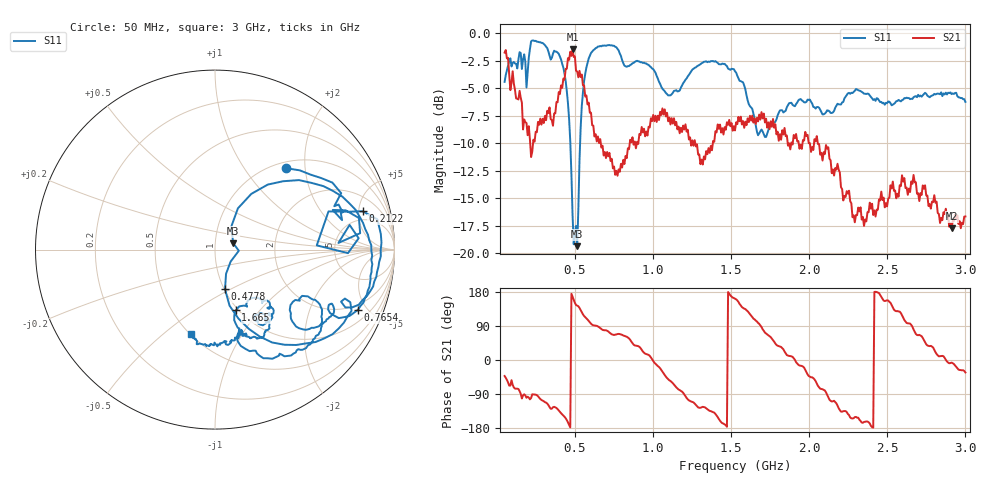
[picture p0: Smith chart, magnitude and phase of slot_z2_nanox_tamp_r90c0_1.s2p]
! nanovna_capture.py 2026-10-26T21:39:05+0900
! NanoVNA-F_V2 fw 0.6.0 SN 4A3639384505514B
! cal: load open short thru cal'ed  over 50000000-3000000000 Hz, 201 points
! points 401, avg 4
! slot line z=1.6, tampered Nano X, 90 deg (length along slot, USB toward PORT 1), centred
# HZ S RI R 50
! S12 and S22 are not measured (written as 0)
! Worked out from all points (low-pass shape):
!   401 points, 50 MHz to 3 GHz, reference 50 ohm
!   highest |S21| = -1.45 dB at 485.1 MHz (marker M1); lowest = -17.8 dB at 2.912 GHz (marker M2)
!   |S21| within 3 dB of the highest: start of sweep to 83.11 MHz; 423.1 MHz to 549.5 MHz (126.4 MHz wide, 26 % of centre) (the widest 2 of 3)
!   lowest |S11| = -19.4 dB at 514.6 MHz (marker M3), VSWR 1.24, Z = 61.1 + j4.42 ohm
!   |S11| at or under -10 dB: 470.8 MHz to 533.3 MHz (62.52 MHz wide, 12.5 % of centre)
!   S12 and S22 are empty: the file has one direction only
!   S11 on the Smith chart (normalised r, x): 50 MHz: 1.12, +1.59; 212.2 MHz: 3.61, +5.52; 477.8 MHz: 1.01, -0.47; 765.4 MHz: 1.64, -4.36; 1.665 GHz: 0.97, -0.76; 3 GHz: 0.51, -0.63
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5e7  0.3949 0.4537  0.6048 -0.5496  0 0  0 0
1.75375e8  0.8004 0.0632  -0.00361 -0.4058  0 0  0 0
2.1225e8  0.8218 0.2136  -0.0788 -0.3182  0 0  0 0
2.78625e8  0.8987 -0.1515  -0.0913 -0.3989  0 0  0 0
4.11375e8  0.5602 -0.515  -0.4464 -0.3697  0 0  0 0
4.7775e8  0.0558 -0.2211  -0.7866 0.0702  0 0  0 0
4.85125e8  0.0615 -0.1351  -0.8248 0.1875  0 0  0 0
5.14625e8  0.1014 0.0357  -0.5392 0.3987  0 0  0 0
5.44125e8  0.2942 0.3624  -0.3798 0.5271  0 0  0 0
6.17875e8  0.8247 0.1489  -0.0107 0.3802  0 0  0 0
7.65375e8  0.7965 -0.3356  0.0909 0.2188  0 0  0 0
1.03825e9  0.4397 -0.4125  0.3825 -0.1275  0 0  0 0
1.207875e9  0.5483 -0.2791  -0.0367 -0.3837  0 0  0 0
1.525e9  0.2917 -0.6055  -0.3437 0.1128  0 0  0 0
1.665125e9  0.1157 -0.3385  -0.0836 0.4039  0 0  0 0
1.842125e9  0.3037 -0.3197  0.343 0.1418  0 0  0 0
2.019125e9  0.2421 -0.4134  0.2121 -0.2176  0 0  0 0
2.196125e9  0.2756 -0.3865  -0.1562 -0.1725  0 0  0 0
2.51325e9  0.1421 -0.4672  -0.1598 0.08  0 0  0 0
2.668125e9  0.1109 -0.5  0.0375 0.2237  0 0  0 0
2.9115e9  -0.0544 -0.5263  0.1286 -0.0154  0 0  0 0
3e9  -0.131 -0.47  0.1233 -0.0797  0 0  0 0
